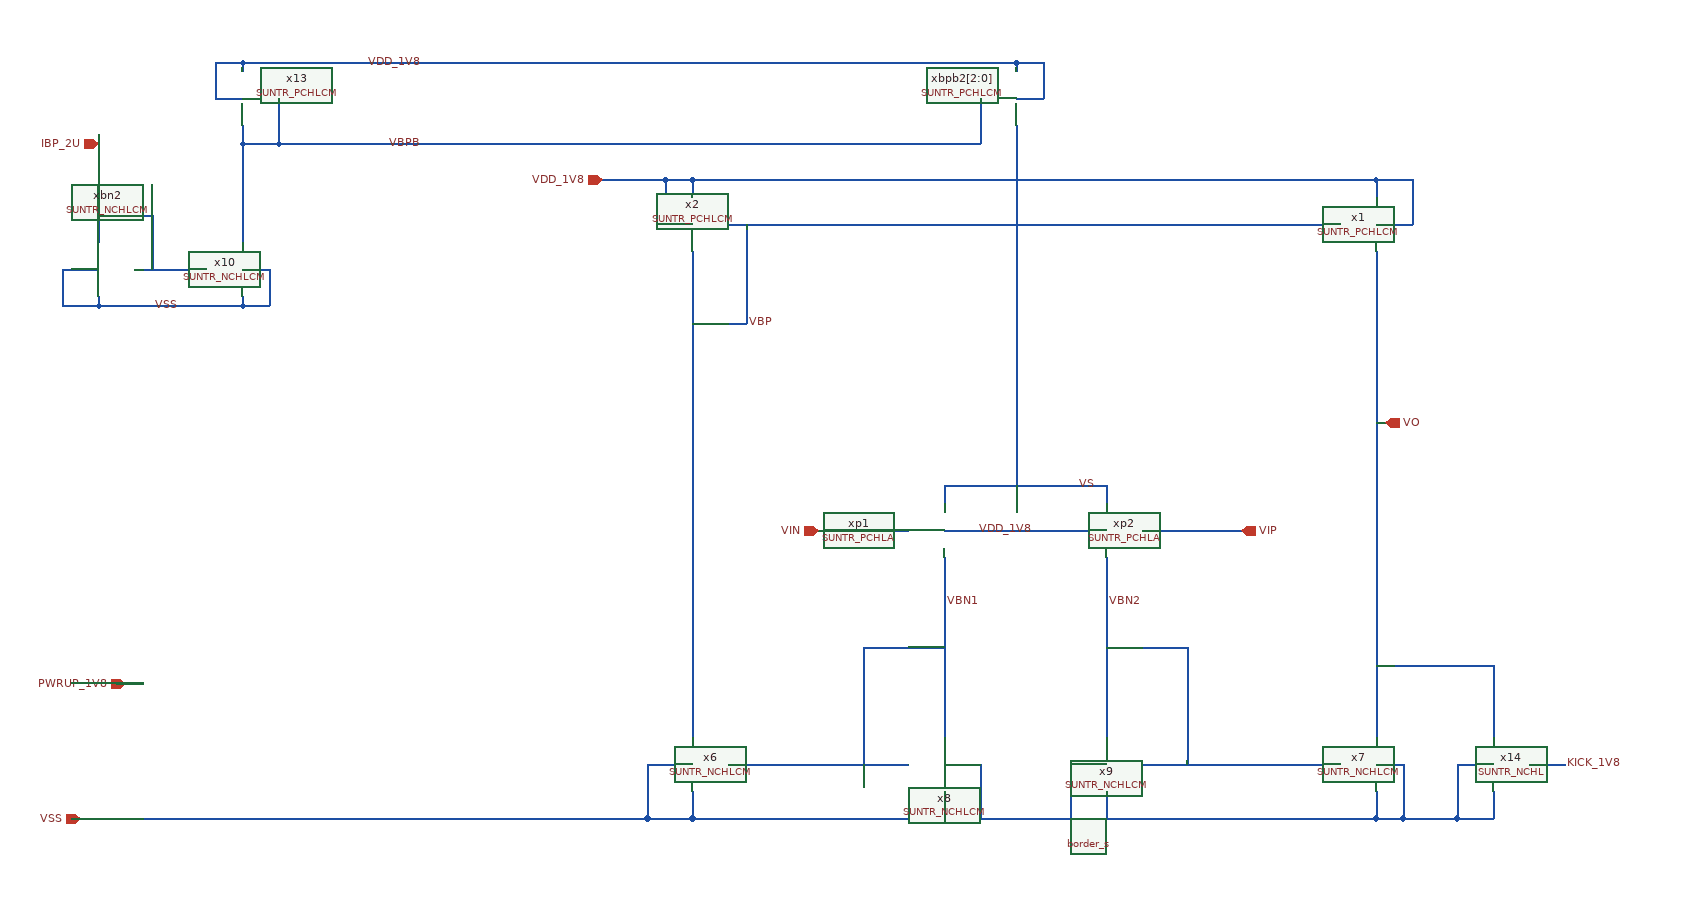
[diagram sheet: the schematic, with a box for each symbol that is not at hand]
v {xschem version=3.0.0 file_version=1.2 }
G {}
K {}
V {}
S {}
E {}
N 190 -810 190 -610 {
lab=VBN1}
N 370 -810 370 -610 {
lab=VBN2}
N 190 -550 190 -520 {
lab=VSS}
N 190 -520 670 -520 {
lab=VSS}
N 670 -550 670 -520 {
lab=VSS}
N 410 -580 630 -580 {
lab=VBN2}
N 370 -550 370 -520 {
lab=VSS}
N -90 -550 -90 -520 {
lab=VSS}
N -90 -520 190 -520 {
lab=VSS}
N -140 -580 -90 -580 {
lab=VSS}
N -140 -580 -140 -520 {
lab=VSS}
N -140 -520 -90 -520 {
lab=VSS}
N -50 -580 150 -580 {
lab=VBN1}
N 100 -710 190 -710 {
lab=VBN1}
N 100 -710 100 -580 {
lab=VBN1}
N 370 -710 460 -710 {
lab=VBN2}
N 460 -710 460 -580 {
lab=VBN2}
N 190 -890 190 -870 {
lab=VS}
N 190 -890 370 -890 {
lab=VS}
N 370 -890 370 -870 {
lab=VS}
N 190 -840 370 -840 {
lab=VDD_1V8}
N -90 -1150 -90 -610 {
lab=VBP}
N -50 -1180 630 -1180 {
lab=VBP}
N -90 -1230 -90 -1210 {
lab=VDD_1V8}
N -90 -1230 670 -1230 {
lab=VDD_1V8}
N 670 -1230 670 -1210 {
lab=VDD_1V8}
N 670 -1180 710 -1180 {
lab=VDD_1V8}
N 710 -1230 710 -1180 {
lab=VDD_1V8}
N 670 -1230 710 -1230 {
lab=VDD_1V8}
N -120 -1180 -90 -1180 {
lab=VDD_1V8}
N -120 -1230 -120 -1180 {
lab=VDD_1V8}
N -120 -1230 -90 -1230 {
lab=VDD_1V8}
N 670 -1150 670 -1130 {
lab=VO}
N 670 -1130 670 -610 {
lab=VO}
N -190 -1230 -120 -1230 {
lab=VDD_1V8}
N -90 -1070 -30 -1070 {
lab=VBP}
N -30 -1180 -30 -1070 {
lab=VBP}
N 670 -960 680 -960 {
lab=VO}
N 670 -580 700 -580 {
lab=VSS}
N 700 -580 700 -520 {
lab=VSS}
N 330 -580 370 -580 {
lab=VSS}
N 330 -580 330 -520 {
lab=VSS}
N 190 -580 230 -580 {
lab=VSS}
N 230 -580 230 -520 {
lab=VSS}
N -780 -520 -140 -520 {
lab=VSS}
N -730 -670 -700 -670 {
lab=PWRUP_1V8}
N 120 -840 150 -840 {
lab=VIN}
N 270 -1000 270 -890 {
lab=VS}
N 670 -520 700 -520 {
lab=VSS}
N -750 -1280 -750 -1160 {
lab=IBP_2U}
N -790 -1130 -750 -1130 {
lab=VSS}
N -790 -1130 -790 -1090 {
lab=VSS}
N -790 -1090 -750 -1090 {
lab=VSS}
N -750 -1100 -750 -1090 {
lab=VSS}
N -710 -1130 -630 -1130 {
lab=IBP_2U}
N -750 -1090 -590 -1090 {
lab=VSS}
N -590 -1100 -590 -1090 {
lab=VSS}
N -590 -1130 -560 -1130 {
lab=VSS}
N -560 -1130 -560 -1090 {
lab=VSS}
N -590 -1090 -560 -1090 {
lab=VSS}
N -690 -1190 -690 -1130 {
lab=IBP_2U}
N -750 -1190 -690 -1190 {
lab=IBP_2U}
N -620 -1320 -590 -1320 {
lab=VDD_1V8}
N -620 -1360 -620 -1320 {
lab=VDD_1V8}
N -620 -1360 -590 -1360 {
lab=VDD_1V8}
N -590 -1360 -590 -1350 {
lab=VDD_1V8}
N 270 -1320 300 -1320 {
lab=VDD_1V8}
N 300 -1360 300 -1320 {
lab=VDD_1V8}
N 270 -1360 300 -1360 {
lab=VDD_1V8}
N 270 -1360 270 -1350 {
lab=VDD_1V8}
N -590 -1290 -590 -1270 {
lab=VBPB}
N -590 -1270 -550 -1270 {
lab=VBPB}
N -550 -1320 -550 -1270 {
lab=VBPB}
N -550 -1270 230 -1270 {
lab=VBPB}
N 230 -1320 230 -1270 {
lab=VBPB}
N -590 -1360 270 -1360 {
lab=VDD_1V8}
N 270 -1290 270 -1000 {
lab=VS}
N 40 -840 70 -840 {
lab=VIN}
N 70 -840 120 -840 {
lab=VIN}
N 490 -840 520 -840 {
lab=VIP}
N 410 -840 490 -840 {
lab=VIP}
N -590 -1270 -590 -1160 {
lab=VBPB}
N 760 -580 800 -580 {
lab=VSS}
N 760 -580 760 -520 {
lab=VSS}
N 800 -550 800 -520 {
lab=VSS}
N 760 -520 800 -520 {
lab=VSS}
N 700 -520 760 -520 {
lab=VSS}
N 800 -690 800 -610 {
lab=VO}
N 670 -690 800 -690 {
lab=VO}
N 840 -580 880 -580 {
lab=KICK_1V8}
C {cborder/border_s.sym} 400 -480 0 0 {}
C {SUN_TR_SKY130NM/SUNTR_PCHLCM.sym} 630 -1180 0 0 {name=x1 xoffset=0 yoffset=0 angle=0 M=1}
C {SUN_TR_SKY130NM/SUNTR_PCHLCM.sym} -50 -1180 0 1 {name=x2 xoffset=0 yoffset=0 angle=0 M=1}
C {SUN_TR_SKY130NM/SUNTR_NCHLCM.sym} 630 -580 0 0 {name=x7 xoffset=0 yoffset=0 angle=0 M=1}
C {SUN_TR_SKY130NM/SUNTR_NCHLCM.sym} -50 -580 0 1 {name=x6 xoffset=0 yoffset=0 angle=0 M=1}
C {SUN_TR_SKY130NM/SUNTR_NCHLCM.sym} 150 -580 0 0 {name=x8 xoffset=0 yoffset=0 angle=0 M=1}
C {SUN_TR_SKY130NM/SUNTR_NCHLCM.sym} 410 -580 0 1 {name=x9 xoffset=0 yoffset=0 angle=0 M=1}
C {SUN_TR_SKY130NM/SUNTR_PCHLA.sym} 150 -840 0 0 {name=xp1 xoffset=0 yoffset=0 angle=0 M=100}
C {SUN_TR_SKY130NM/SUNTR_PCHLA.sym} 410 -840 0 1 {name=xp2 xoffset=0 yoffset=0 angle=0 M=100}
C {devices/ipin.sym} -190 -1230 0 0 {name=p1 lab=VDD_1V8}
C {devices/lab_pin.sym} -30 -1070 0 1 {name=l2 sig_type=std_logic lab=VBP}
C {devices/opin.sym} 680 -960 0 0 {name=p2 lab=VO}
C {devices/lab_pin.sym} 190 -760 0 1 {name=l6 sig_type=std_logic lab=VBN1}
C {devices/lab_pin.sym} 370 -760 0 1 {name=l7 sig_type=std_logic lab=VBN2}
C {devices/ipin.sym} -770 -520 0 0 {name=p3 lab=VSS}
C {devices/ipin.sym} -720 -670 0 0 {name=p4 lab=PWRUP_1V8}
C {devices/ipin.sym} 50 -840 0 0 {name=p5 lab=VIN}
C {devices/ipin.sym} 520 -840 0 1 {name=p6 lab=VIP}
C {devices/ipin.sym} -750 -1270 1 0 {name=p7 lab=IBP_2U}
C {SUN_TR_SKY130NM/SUNTR_NCHLCM.sym} -710 -1130 0 1 {name=xbn2 xoffset=0 yoffset=0 angle=0 M=1}
C {SUN_TR_SKY130NM/SUNTR_NCHLCM.sym} -630 -1130 0 0 {name=x10 xoffset=0 yoffset=0 angle=0 M=1}
C {SUN_TR_SKY130NM/SUNTR_PCHLCM.sym} -550 -1320 0 1 {name=x13 xoffset=0 yoffset=0 angle=0 M=1}
C {SUN_TR_SKY130NM/SUNTR_PCHLCM.sym} 230 -1320 0 0 {name=xbpb2[2:0] xoffset=0 yoffset=0 angle=0 M=1}
C {devices/lab_wire.sym} 290 -840 0 0 {name=l24 sig_type=std_logic lab=VDD_1V8}
C {devices/lab_wire.sym} -390 -1360 0 0 {name=l25 sig_type=std_logic lab=VDD_1V8}
C {devices/lab_wire.sym} -660 -1090 0 0 {name=l26 sig_type=std_logic lab=VSS}
C {devices/lab_wire.sym} -390 -1270 0 0 {name=l29 sig_type=std_logic lab=VBPB}
C {devices/lab_wire.sym} 360 -890 0 0 {name=l30 sig_type=std_logic lab=VS}
C {SUN_TR_SKY130NM/SUNTR_NCHL.sym} 840 -580 0 1 {name=x14 xoffset=0 yoffset=0 angle=0 M=1}
C {devices/lab_pin.sym} 880 -580 0 1 {name=l34 sig_type=std_logic lab=KICK_1V8}
